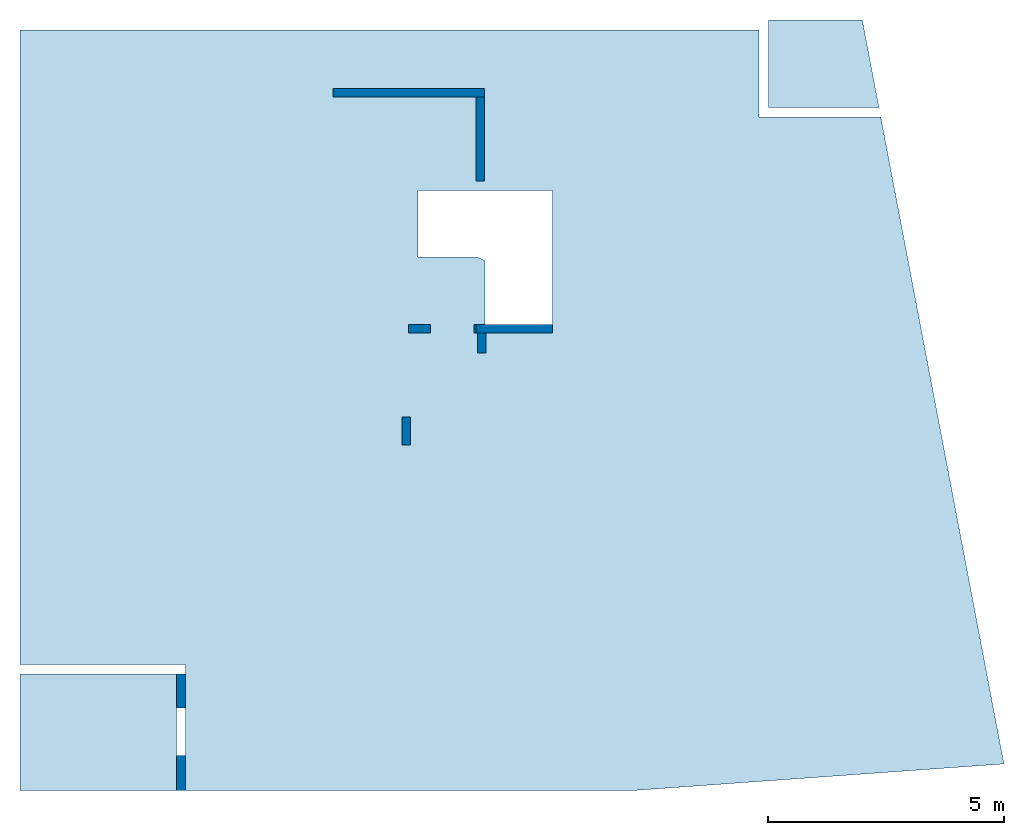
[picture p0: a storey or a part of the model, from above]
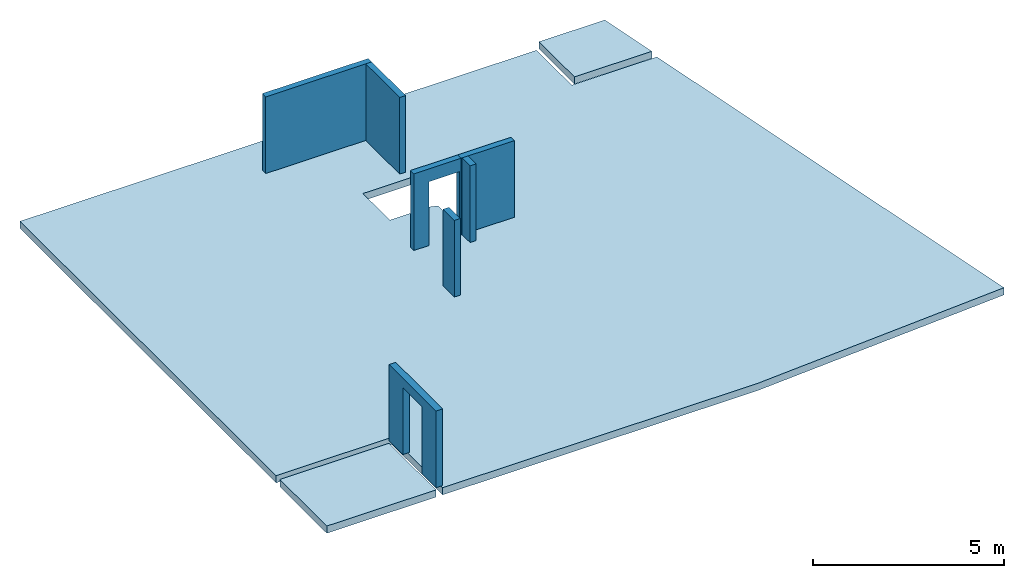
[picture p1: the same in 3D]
Properties of the parts of a building model (IFC2X3)

# File
Description: ViewDefinition [CoordinationView_V2.0]
File name: xxx
Time: 2019-03-27T17:23:22
Written by: The EXPRESS Data Manager Version 5.02.0100.07 : 28 Aug 2013
Made in: 20160225_1515(x64) - Exporter 17.0.416.0 - Alternate UI 17.12.14.0
Comment: STEP Physical File produced by: The EXPRESS Data Manager Version 5.02.0100.07 : 28 Aug 2013 * Module: EDMstepFileFactory/EDMstandAlone * Creation date: Wed Mar 27 17:23:22 2019 * Host: PC-BUREAU-Blandine * Database: C:\Users\Blandine\AppData\Local\Temp\{AA41DF01-AA26-42AC-969A-92ED7AF7943F}\ifc * Database version: 5507 * Database creation date: Wed Mar 27 17:23:17 2019 * Schema: IFC2X3 * Model: DataRepository.ifc * Model creation date: Wed Mar 27 17:23:18 2019 * Header model: DataRepository.ifc_HeaderModel * Header model creation date: Wed Mar 27 17:23:18 2019 * EDMuser: sdai-user * EDMgroup: sdai-group * License ID and type: 5605 : Permanent license. Expiry date: * EDMstepFileFactory options: 020000

# IfcProject, xxx
LongName: 52 logements collectifs; Phase: Etat du projet

# IfcSite, Default
RefLatitude: 48, 51, 57, 604064; RefLongitude: 2, 19, 58, 799800; RefElevation: 1200 cm

# IfcBuilding
Pset_BuildingCommon - NumberOfStoreys: 5

# IfcBuildingStorey (5)
Name | LongName | Elevation (cm)
Fondations | Fondations | -60
Rdc | Rdc | 0
R+1 | R+1 | 272
R+2 | R+2 | 544
R+3 | R+3 | 821

# IfcBeam: 20 x 20 ht, BB_BANDE NOYEE:20 x 20 ht:796053
In: R+1
Material: Béton_C25/30
Pset_BeamCommon - LoadBearing: yes; IsExternal: no; Slope: 0 deg; Reference: 20 x 20 ht; Span: 153 cm

# IfcBeam: 20x35 ht, BB_POUTRE RECTANGULAIRE:20x35 ht:840110
In: R+2
Material: Béton_C25/30
Pset_BeamCommon - LoadBearing: yes; IsExternal: no; Reference: 20x35 ht; Slope: 0 deg; Span: 50.0001 cm

# IfcBeam: BB_BN_RECTANGULAIRE (3)
In: R+1
Material: Béton_C25/30
Pset_BeamCommon - LoadBearing: yes; IsExternal: no; Slope: 0 deg; Reference: BB_BN_RECTANGULAIRE
Name (BB_BANDE NOYEE:BB_BN_RECTANGULAIRE:...) | Span (cm)
795771 | 139.247
795805 | 130
795938 | 187.675

# IfcBeam: BB_POUTRE RECTANGULAIRE:18x62:856170 (2)
In: R+3
Material: Béton_C25/30
Pset_BeamCommon - LoadBearing: yes; IsExternal: no; Slope: 0 deg; Reference: 18x62
Name (BB_POUTRE RECTANGULAIRE:18x62:...) | Span (cm)
855576 | 126.758
855700 | 103.5

# IfcBeam: BB_POUTRE RECTANGULAIRE:20x35 ht:798498 (2)
In: R+1
Material: Béton_C25/30
Pset_BeamCommon - LoadBearing: yes; IsExternal: no; Reference: 20x35 ht; Slope: 0 deg
Name (BB_POUTRE RECTANGULAIRE:20x35 ht:...) | Span (cm)
776936 | 384.387
777788 | 398

# IfcBeam: BB_POUTRE RECTANGULAIRE:20x62:840547 (2)
In: R+3
Material: Béton_C25/30
Pset_BeamCommon - LoadBearing: yes; IsExternal: no; Slope: 0 deg; Reference: 20x62
Name (BB_POUTRE RECTANGULAIRE:20x62:...) | Span (cm)
840175 | 52.2627
840298 | 171.406

# IfcBeam: BB_POUTRE RECTANGULAIRE:30x60:798424, BB_POUTRE RECTANGULAIRE:30x60:796752
In: R+1
Material: Béton_C25/30
Pset_BeamCommon - LoadBearing: yes; IsExternal: no; Slope: 0 deg; Reference: 30x60; Span: 571.486 cm

# IfcBeam: MR_POUTRE RECTANGULAIRE:25x60_C25/30:791405, MR_POUTRE RECTANGULAIRE:25x60_C25/30:791472
In: R+1
Material: Béton_C25/30
Pset_BeamCommon - LoadBearing: yes; IsExternal: no; Slope: 0 deg; Reference: 25x60_C25/30; Span: 325.113 cm

# IfcBeam: MR_POUTRE RECTANGULAIRE:40x60_C25/30:790994, MR_POUTRE RECTANGULAIRE:40x60_C25/30:791073
In: R+1
Material: Béton_C25/30
Pset_BeamCommon - LoadBearing: yes; IsExternal: no; Slope: 0 deg; Reference: 40x60_C25/30; Span: 511.406 cm

# IfcBuildingElementProxy: ST 1, ST:ST 1:877627
In: R+1
Type - Material: ALPHI_Acier, ALPHI_Acier laque bleu foncé, ALPHI_Fourrures bois
Pset_BuildingElementProxyCommon - Reference: ST 1

# IfcColumn: POTEAU_18x20_C25/30, MR_POTEAU RECTANGULAIRE:POTEAU_18x20_C25/30:854734
In: R+2
Type - ElementType: POTEAU_18x20_C25/30; PredefinedType: COLUMN; Material: Béton_C25/30
Pset_ColumnCommon - LoadBearing: yes; IsExternal: no; Reference: POTEAU_18x20_C25/30

# IfcColumn: POTEAU_18x35_C25/30, MR_POTEAU RECTANGULAIRE:POTEAU_18x35_C25/30:776539
In: Fondations
Type - ElementType: POTEAU_18x35_C25/30; PredefinedType: COLUMN; Material: Béton_C25/30
Pset_ColumnCommon - LoadBearing: yes; IsExternal: no; Reference: POTEAU_18x35_C25/30

# IfcColumn: POTEAU_20x20_C25/30, MR_POTEAU RECTANGULAIRE:POTEAU_20x20_C25/30:839051
In: R+2
Type - ElementType: POTEAU_20x20_C25/30; PredefinedType: COLUMN; Material: Béton_C25/30
Pset_ColumnCommon - LoadBearing: yes; IsExternal: no; Reference: POTEAU_20x20_C25/30

# IfcColumn: POTEAU_20x57_C25/30, MR_POTEAU RECTANGULAIRE:POTEAU_20x57_C25/30:768363
In: Fondations
Type - ElementType: POTEAU_20x57_C25/30; PredefinedType: COLUMN; Material: Béton_C25/30
Pset_ColumnCommon - LoadBearing: yes; IsExternal: no; Reference: POTEAU_20x57_C25/30

# IfcRailing: 2F1900 (2)
In: R+2
Type - Material: Montant métallique, Contreplaqué, finition, Clôture - Grillage
Pset_RailingCommon - IsExternal: no; Reference: 2F1900
Name (2F1900:2F1900:...)
845580
878391

# IfcReinforcingBar: Barre d'armature:HA6 (Fe400):218264 (4)
In: R+2
NominalDiameter: 0.6 cm; CrossSectionArea: 0.0000282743 m2; BarLength: 15 cm; Group: Barre d'armature:HA6 (Fe400)
Pset_ReinforcingBarBendingsISOCD3766Common - ISOCD3766ShapeCode: 00; ISOCD3766ShapeParameter_a: 15 cm; ISOCD3766ShapeParameter_R: 5 cm
Name (Barre d'armature:HA6 (Fe400) : Forme 00:840953:...)
 1
 2
 3
 4

# IfcSlab: Sol:DALLE_20_C25/30 (11)
PredefinedType: FLOOR; Material: Béton_C25/30 20 cm
Pset_SlabCommon - LoadBearing: yes; IsExternal: no; Reference: DALLE_20_C25/30; ThermalTransmittance: 5.23 kg/K/s3
Name (Sol:DALLE_20_C25/30:...) | In | PitchAngle (deg)
778403 | R+1
778712 | R+1 | 0
779417 | R+1 | 0
779905 | R+1 | 0
807110 | R+1 | 0
831430 | R+2 | 0
833845 | R+2
834807 | R+2 | 0
834946 | R+2 | 0
835070 | R+2 | 0
838339 | R+3

# IfcSlab: Sol:DALLE_23_C25/30 (3)
In: Rdc
PredefinedType: FLOOR; Material: Béton_C25/30 23 cm
Pset_SlabCommon - LoadBearing: yes; Reference: DALLE_23_C25/30; IsExternal: no; ThermalTransmittance: 4.54783 kg/K/s3
Name (Sol:DALLE_23_C25/30:...) | PitchAngle (deg)
764130
765006 | 0
765290 | 0

# IfcWall: Mur de base:VOILE_20_C25/30, Mur de base:VOILE_20_C25/30:767469
In: R+1
Type - PredefinedType: STANDARD; Material: Béton_C25/30 20 cm
Pset_WallCommon - LoadBearing: yes; ExtendToStructure: yes; IsExternal: yes; Reference: VOILE_20_C25/30; ThermalTransmittance: 5.23 kg/K/s3

# IfcWallStandardCase: Mur de base:BBM_20 (42)
Type - PredefinedType: STANDARD; Material: Maçonnerie - Béton 20 cm
Pset_WallCommon - Reference: BBM_20; LoadBearing: yes; IsExternal: yes
Name (Mur de base:BBM_20:...) | In | ExtendToStructure
760492 | Fondations | yes
760505 | Fondations | yes
760538 | Fondations | yes
760551 | Rdc | yes
760615 | Fondations | yes
760917 | Fondations | yes
761049 | Fondations | yes
761123 | Fondations | yes
761185 | Fondations | yes
761221 | Fondations | yes
761283 | Fondations | yes
766321 | R+1 | yes
766342 | R+1 | yes
766355 | R+1 | yes
766370 | R+1 | yes
766735 | R+1 | yes
766746 | R+1 | yes
766757 | R+1 | yes
766832 | R+1 | yes
766856 | R+1 | yes
766871 | R+1 | yes
767013 | R+1 | yes
767026 | R+1 | yes
767067 | R+1 | yes
785922 | R+1 | yes
810482 | R+1 | no
810900 | R+1 | no
811217 | R+1 | no
813793 | R+2 | yes
814187 | R+2 | yes
814635 | R+2 | yes
814945 | R+2 | yes
815187 | R+2 | yes
815828 | R+2 | yes
816004 | R+2 | yes
816186 | R+2 | yes
816642 | R+2 | yes
816872 | R+2 | yes
817103 | R+2 | yes
817279 | R+2 | yes
817695 | R+2 | yes
826811 | R+2 | yes

# IfcWallStandardCase: Mur de base:VOILE_16_C25/30 (3)
In: Fondations
Type - PredefinedType: STANDARD; Material: Béton_C25/30 16 cm
Pset_WallCommon - LoadBearing: yes; ExtendToStructure: yes; IsExternal: yes; Reference: VOILE_16_C25/30; ThermalTransmittance: 6.5375 kg/K/s3
Name (Mur de base:VOILE_16_C25/30:...)
762961
762974
762987

# IfcWallStandardCase: Mur de base:VOILE_18_C25/30 (19)
Type - PredefinedType: STANDARD; Material: Béton_C25/30 18 cm
Pset_WallCommon - LoadBearing: yes; ExtendToStructure: yes; IsExternal: yes; Reference: VOILE_18_C25/30; ThermalTransmittance: 5.81111 kg/K/s3
Name (Mur de base:VOILE_18_C25/30:...) | In
762639 | Rdc
762652 | Rdc
762817 | Fondations
762843 | Rdc
762856 | Fondations
762903 | Fondations
762916 | Rdc
762929 | Rdc
762942 | Rdc
763933 | Fondations
767522 | R+1
767589 | R+1
767606 | R+1
767723 | R+1
767773 | R+1
767860 | R+1
767871 | R+1
767899 | R+1
767930 | R+1

# IfcWallStandardCase: Mur de base:VOILE_20_C25/30 (44)
Type - PredefinedType: STANDARD; Material: Béton_C25/30 20 cm
Pset_WallCommon - LoadBearing: yes; IsExternal: yes; Reference: VOILE_20_C25/30; ThermalTransmittance: 5.23 kg/K/s3
Name (Mur de base:VOILE_20_C25/30:...) | In | ExtendToStructure
761440 | Fondations | yes
761476 | Fondations | yes
761640 | Fondations | yes
761653 | Fondations | yes
761668 | Fondations | yes
761702 | Fondations | yes
761898 | Fondations | yes
762039 | Fondations | yes
762076 | Fondations | yes
762665 | Fondations | yes
762890 | Fondations | yes
763157 | Fondations | yes
763174 | Fondations | yes
767385 | R+1 | yes
767399 | R+1 | yes
767662 | R+1 | yes
782717 | R+1 | yes
803848 | Fondations | yes
804052 | Fondations | yes
806147 | R+1 | yes
808177 | R+1 | yes
811615 | R+1 | yes
818838 | R+2 | yes
819003 | R+2 | yes
819200 | R+2 | yes
819416 | R+2 | yes
819485 | R+2 | yes
819584 | R+2 | yes
819769 | R+2 | yes
820013 | R+2 | yes
820344 | R+2 | yes
820456 | R+2 | yes
820573 | R+2 | yes
820764 | R+2 | yes
820825 | R+2 | yes
820904 | R+2 | yes
821051 | R+2 | yes
821217 | R+2 | yes
827753 | R+2 | yes
870166 | R+3 | no
870427 | R+3 | no
870636 | R+3 | no
870853 | R+3 | no
870970 | R+3 | no
